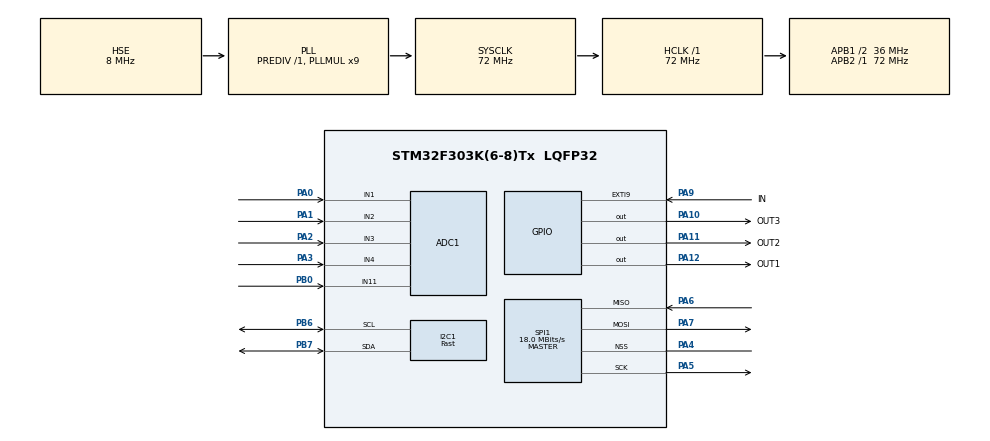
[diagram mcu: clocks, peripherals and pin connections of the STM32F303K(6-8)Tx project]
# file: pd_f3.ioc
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ADC1.Channel-0\#ChannelRegularConversion=ADC_CHANNEL_1
ADC1.Channel-1\#ChannelRegularConversion=ADC_CHANNEL_2
ADC1.Channel-2\#ChannelRegularConversion=ADC_CHANNEL_3
ADC1.Channel-3\#ChannelRegularConversion=ADC_CHANNEL_4
ADC1.Channel-4\#ChannelRegularConversion=ADC_CHANNEL_11
ADC1.ClockPrescaler=ADC_CLOCKPRESCALER_PCLK_DIV2
ADC1.ContinuousConvMode=ENABLE
ADC1.DMAContinuousRequests=ENABLE
ADC1.DataAlign=ADC_DATAALIGN_RIGHT
ADC1.DiscontinuousConvMode=DISABLE
ADC1.EOCSelection=EOC_SEQ_CONV
ADC1.EnableAnalogWatchDog1=false
ADC1.EnableAnalogWatchDog2=false
ADC1.EnableAnalogWatchDog3=false
ADC1.EnableInjectedConversion=ENABLE
ADC1.EnableRegularConversion=ENABLE
ADC1.ExternalTrigConvEdge=ADC_EXTERNALTRIGCONVEDGE_NONE
ADC1.InjNumberOfConversion=0
ADC1.LowPowerAutoWait=DISABLE
ADC1.NbrOfConversion=5
ADC1.NbrOfConversionFlag=1
ADC1.Offset-0\#ChannelRegularConversion=0
ADC1.Offset-1\#ChannelRegularConversion=0
ADC1.Offset-2\#ChannelRegularConversion=0
ADC1.Offset-3\#ChannelRegularConversion=0
ADC1.Offset-4\#ChannelRegularConversion=0
ADC1.OffsetNumber-0\#ChannelRegularConversion=ADC_OFFSET_NONE
ADC1.OffsetNumber-1\#ChannelRegularConversion=ADC_OFFSET_NONE
ADC1.OffsetNumber-2\#ChannelRegularConversion=ADC_OFFSET_NONE
ADC1.OffsetNumber-3\#ChannelRegularConversion=ADC_OFFSET_NONE
ADC1.OffsetNumber-4\#ChannelRegularConversion=ADC_OFFSET_NONE
ADC1.Overrun=OVR_DATA_OVERWRITTEN
ADC1.Rank-0\#ChannelRegularConversion=1
ADC1.Rank-1\#ChannelRegularConversion=2
ADC1.Rank-2\#ChannelRegularConversion=3
ADC1.Rank-3\#ChannelRegularConversion=4
ADC1.Rank-4\#ChannelRegularConversion=5
ADC1.Resolution=ADC_RESOLUTION12b
ADC1.SamplingTime-0\#ChannelRegularConversion=ADC_SAMPLETIME_61CYCLES_5
ADC1.SamplingTime-1\#ChannelRegularConversion=ADC_SAMPLETIME_61CYCLES_5
ADC1.SamplingTime-2\#ChannelRegularConversion=ADC_SAMPLETIME_61CYCLES_5
ADC1.SamplingTime-3\#ChannelRegularConversion=ADC_SAMPLETIME_61CYCLES_5
ADC1.SamplingTime-4\#ChannelRegularConversion=ADC_SAMPLETIME_61CYCLES_5
ADC1.ScanConvMode=ADC_SCAN_ENABLE
ADC1.master=1
Dma.ADC1.3.Direction=DMA_PERIPH_TO_MEMORY
Dma.ADC1.3.Instance=DMA1_Channel1
Dma.ADC1.3.MemDataAlignment=DMA_MDATAALIGN_HALFWORD
Dma.ADC1.3.MemInc=DMA_MINC_ENABLE
Dma.ADC1.3.Mode=DMA_CIRCULAR
Dma.ADC1.3.PeriphDataAlignment=DMA_PDATAALIGN_HALFWORD
Dma.ADC1.3.PeriphInc=DMA_PINC_DISABLE
Dma.ADC1.3.Priority=DMA_PRIORITY_HIGH
Dma.I2C1_RX.0.DMA_Remap=HAL_REMAPDMA_I2C1_RX_DMA1_CH5
Dma.I2C1_RX.0.Direction=DMA_PERIPH_TO_MEMORY
Dma.I2C1_RX.0.Instance=DMA1_Channel5
Dma.I2C1_RX.0.MemDataAlignment=DMA_MDATAALIGN_BYTE
Dma.I2C1_RX.0.MemInc=DMA_MINC_ENABLE
Dma.I2C1_RX.0.Mode=DMA_NORMAL
Dma.I2C1_RX.0.PeriphDataAlignment=DMA_PDATAALIGN_BYTE
Dma.I2C1_RX.0.PeriphInc=DMA_PINC_DISABLE
Dma.I2C1_RX.0.Priority=DMA_PRIORITY_VERY_HIGH
Dma.I2C1_TX.1.DMA_Remap=HAL_REMAPDMA_I2C1_TX_DMA1_CH2
Dma.I2C1_TX.1.Direction=DMA_MEMORY_TO_PERIPH
Dma.I2C1_TX.1.Instance=DMA1_Channel2
Dma.I2C1_TX.1.MemDataAlignment=DMA_MDATAALIGN_BYTE
Dma.I2C1_TX.1.MemInc=DMA_MINC_ENABLE
Dma.I2C1_TX.1.Mode=DMA_NORMAL
Dma.I2C1_TX.1.PeriphDataAlignment=DMA_PDATAALIGN_BYTE
Dma.I2C1_TX.1.PeriphInc=DMA_PINC_DISABLE
Dma.I2C1_TX.1.Priority=DMA_PRIORITY_VERY_HIGH
Dma.Request0=I2C1_RX
Dma.Request1=I2C1_TX
Dma.Request2=SPI1_TX
Dma.Request3=ADC1
Dma.SPI1_TX.2.Direction=DMA_MEMORY_TO_PERIPH
Dma.SPI1_TX.2.Instance=DMA1_Channel3
Dma.SPI1_TX.2.MemDataAlignment=DMA_MDATAALIGN_HALFWORD
Dma.SPI1_TX.2.MemInc=DMA_MINC_ENABLE
Dma.SPI1_TX.2.Mode=DMA_NORMAL
Dma.SPI1_TX.2.PeriphDataAlignment=DMA_PDATAALIGN_HALFWORD
Dma.SPI1_TX.2.PeriphInc=DMA_PINC_DISABLE
Dma.SPI1_TX.2.Priority=DMA_PRIORITY_LOW
FREERTOS.BinarySemaphores01=semI2cBusy
FREERTOS.HEAP_NUMBER=1
FREERTOS.Queues01=qI2cTrans,10,uint32_t,NULL;qAnalyzeCom,10,uint32_t,NULL;qAnalyzeConf,1,Configure,NULL
FREERTOS.Tasks01=defaultTask,0,128,StartDefaultTask;analyze,0,256,Analyze;i2cTrans,1,128,I2cTrans
FREERTOS.configIDLE_SHOULD_YIELD=0
FREERTOS.configQUEUE_REGISTRY_SIZE=0
FREERTOS.configTOTAL_HEAP_SIZE=5000
FREERTOS.configUSE_COUNTING_SEMAPHORES=0
FREERTOS.configUSE_MUTEXES=0
FREERTOS.configUSE_RECURSIVE_MUTEXES=0
I2C1.DualAddressMode=I2C_DUALADDRESS_ENABLED
I2C1.GeneralCallMode=I2C_GENERALCALL_DISABLED
I2C1.I2C_Speed_Mode=I2C_Fast
I2C1.OwnAddress2=1
I2C1.Timing=0x0000020B
Mcu.Family=STM32F3
Mcu.Name=STM32F303K(6-8)Tx
Mcu.Package=LQFP32
NVIC.DMA1_Channel1_IRQn=true\:6\:0\:true
NVIC.DMA1_Channel2_IRQn=true\:7\:0\:true
NVIC.DMA1_Channel3_IRQn=true\:6\:0\:true
NVIC.DMA1_Channel5_IRQn=true\:7\:0\:true
NVIC.EXTI9_5_IRQn=true\:5\:0\:false
NVIC.I2C1_ER_IRQn=true\:5\:0\:false
NVIC.I2C1_EV_IRQn=true\:7\:0\:true
NVIC.PriorityGroup=NVIC_PRIORITYGROUP_4
PA0.Mode=IN1-Single-Ended
PA0.Signal=ADC1_IN1
PA1.Mode=IN2-Single-Ended
PA1.Signal=ADC1_IN2
PA10.GPIO_Label=OUT3
PA10.GPIO_PuPd=GPIO_PULLDOWN
PA10.GPIO_Speed=GPIO_SPEED_HIGH
PA10.Signal=GPIO_Output
PA11.GPIO_Label=OUT2
PA11.GPIO_PuPd=GPIO_PULLDOWN
PA11.GPIO_Speed=GPIO_SPEED_HIGH
PA11.Signal=GPIO_Output
PA12.GPIO_Label=OUT1
PA12.GPIO_PuPd=GPIO_PULLDOWN
PA12.GPIO_Speed=GPIO_SPEED_HIGH
PA12.Signal=GPIO_Output
PA13.Mode=JTAG(5-pin)
PA13.Signal=SYS_JTMS-SWDIO
PA14.Mode=JTAG(5-pin)
PA14.Signal=SYS_JTCK-SWCLK
PA15.Mode=JTAG(5-pin)
PA15.Signal=SYS_JTDI
PA2.Mode=IN3-Single-Ended
PA2.Signal=ADC1_IN3
PA3.Mode=IN4-Single-Ended
PA3.Signal=ADC1_IN4
PA4.Mode=NSS_Signal_Hard
PA4.Signal=SPI1_NSS
PA5.Mode=Full_Duplex_Master
PA5.Signal=SPI1_SCK
PA6.Mode=Full_Duplex_Master
PA6.Signal=SPI1_MISO
PA7.Mode=Full_Duplex_Master
PA7.Signal=SPI1_MOSI
PA9.GPIO_Label=IN
PA9.GPIO_ModeDefaultEXTI=GPIO_MODE_IT_RISING
PA9.GPIO_PuPd=GPIO_PULLDOWN
PA9.Signal=GPXTI9
PB0.Mode=IN11-Single-Ended
PB0.Signal=ADC1_IN11
PB3.Mode=JTAG(5-pin)
PB3.Signal=SYS_JTDO-TRACESWO
PB4.Mode=JTAG(5-pin)
PB4.Signal=SYS_NJTRST
PB6.Mode=I2C
PB6.Signal=I2C1_SCL
PB7.Mode=I2C
PB7.Signal=I2C1_SDA
PF0\ /\ OSC_IN.Mode=HSE-External-Oscillator
PF0\ /\ OSC_IN.Signal=RCC_OSC_IN
PF1\ /\ OSC_OUT.Mode=HSE-External-Oscillator
PF1\ /\ OSC_OUT.Signal=RCC_OSC_OUT
ProjectManager.TargetToolchain=SW4STM32
RCC.ADC12PRES=RCC_ADC12PLLCLK_DIV10
RCC.AHBFreq_Value=72000000
RCC.APB1CLKDivider=RCC_HCLK_DIV2
RCC.APB1Freq_Value=36000000
RCC.APB1TimCLKDivider=1
RCC.APB1TimFreq_Value=36000000
RCC.APB2Freq_Value=72000000
RCC.APB2TimFreq_Value=72000000
RCC.CortexFreq_Value=72000000
RCC.HCLKFreq_Value=72000000
RCC.HSE_VALUE=8000000
RCC.HSI_VALUE=8000000
RCC.PLLMUL=RCC_PLL_MUL9
RCC.PLLSourceVirtual=RCC_PLLSOURCE_HSE
RCC.SYSCLKFreq_VALUE=72000000
RCC.SYSCLKSourceVirtual=RCC_SYSCLKSOURCE_PLLCLK
SPI1.BaudRatePrescaler=SPI_BAUDRATEPRESCALER_4
SPI1.CalculateBaudRate=18.0 MBits/s
SPI1.DataSize=SPI_DATASIZE_16BIT
SPI1.Mode=SPI_MODE_MASTER
SPI1.NSS=SPI_NSS_HARD_OUTPUT
SPI1.VirtualNSS=VM_NSSHARD
VP_FREERTOS_VS_ENABLE.Mode=Enabled
board=pd_f3

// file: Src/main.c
/**
 ******************************************************************************
 * File Name          : main.c
 * Description        : Main program body
 ******************************************************************************
 *
 * COPYRIGHT(c) 2016 STMicroelectronics
 *
 * Redistribution and use in source and binary forms, with or without modification,
 * are permitted provided that the following conditions are met:
 *   1. Redistributions of source code must retain the above copyright notice,
 *      this list of conditions and the following disclaimer.
 *   2. Redistributions in binary form must reproduce the above copyright notice,
 *      this list of conditions and the following disclaimer in the documentation
 *      and/or other materials provided with the distribution.
 *   3. Neither the name of STMicroelectronics nor the names of its contributors
 *      may be used to endorse or promote products derived from this software
 *      without specific prior written permission.
 *
 * THIS SOFTWARE IS PROVIDED BY THE COPYRIGHT HOLDERS AND CONTRIBUTORS "AS IS"
 * AND ANY EXPRESS OR IMPLIED WARRANTIES, INCLUDING, BUT NOT LIMITED TO, THE
 * IMPLIED WARRANTIES OF MERCHANTABILITY AND FITNESS FOR A PARTICULAR PURPOSE ARE
 * DISCLAIMED. IN NO EVENT SHALL THE COPYRIGHT HOLDER OR CONTRIBUTORS BE LIABLE
 * FOR ANY DIRECT, INDIRECT, INCIDENTAL, SPECIAL, EXEMPLARY, OR CONSEQUENTIAL
 * DAMAGES (INCLUDING, BUT NOT LIMITED TO, PROCUREMENT OF SUBSTITUTE GOODS OR
 * SERVICES; LOSS OF USE, DATA, OR PROFITS; OR BUSINESS INTERRUPTION) HOWEVER
 * CAUSED AND ON ANY THEORY OF LIABILITY, WHETHER IN CONTRACT, STRICT LIABILITY,
 * OR TORT (INCLUDING NEGLIGENCE OR OTHERWISE) ARISING IN ANY WAY OUT OF THE USE
 * OF THIS SOFTWARE, EVEN IF ADVISED OF THE POSSIBILITY OF SUCH DAMAGE.
 *
 ******************************************************************************
 */
#include "stm32f3xx_hal.h"
#include "cmsis_os.h"
/* USER CODE BEGIN Includes */
#include "configure.h"
/* USER CODE END Includes */

ADC_HandleTypeDef hadc1;
DMA_HandleTypeDef hdma_adc1;

I2C_HandleTypeDef hi2c1;
DMA_HandleTypeDef hdma_i2c1_rx;
DMA_HandleTypeDef hdma_i2c1_tx;

SPI_HandleTypeDef hspi1;
DMA_HandleTypeDef hdma_spi1_tx;

osThreadId defaultTaskHandle;
osThreadId analyzeHandle;
osThreadId i2cTransHandle;
osMessageQId qI2cTransHandle;
osMessageQId qAnalyzeComHandle;
osMailQId qAnalyzeConfHandle;
//osSemaphoreId semI2cBusyHandle;

/* USER CODE BEGIN PV */
/* Private variables ---------------------------------------------------------*/
static uint16_t outOverload[3] = { GPIO_PIN_12 , GPIO_PIN_11, GPIO_PIN_10};	//номера GPIOA выводов, сигнализирующих о перегрузки по току каналов питания МАД
static uint16_t bufData[NUM_ELEM_BUF_DATA] = {1};	//буфер данных, заполняемый показаниями АЦП
static uint16_t* addrBegBufData = bufData;	//адрес начала буфера данных
static uint16_t* addrMeanBufData = bufData + NUM_ELEM_BUF_DATA/2;	//адрес середины буфера данных
static uint16_t* addrEndBufData = bufData + NUM_ELEM_BUF_DATA;	//адрес последнего элемента буфера данных
static struct Sample* addrStopPoint;	//адрес следующей точки остановки мониторинговой программы
static struct Sample* addrCurPoint;	//адрес текущего положения мониторинговой программы
static uint32_t countOfLead;	//счётчик опережения. Используется для определния насколько сегментов мониторинг данных отстал от их заполнения
struct StatusMonitData stMonitData;	//структура, управляющая режимом сбора данных
static struct SecConfigure bufConf;	//буфер, в котором сохраняется полученное по I2C новое значение структуры безопасности
static uint32_t bufCom;	//буфер, в котором сохраняется полученная по I2C очередная команда
static uint32_t identBlockDataComForI2c;	//идентификатор блока данных, пришедшего по i2c
static uint32_t bufI2cTrans = 1;
static bool i2c_is_trans = true;	//флаг режима работы i2c, true - передатчик
/* USER CODE END PV */

void SystemClock_Config(void);
static void MX_GPIO_Init(void);
static void MX_DMA_Init(void);
static void MX_ADC1_Init(void);
static void MX_I2C1_Init(void);
static void MX_SPI1_Init(void);
void Analyze(void const * argument);
void I2cTrans(void const * argument);

/* USER CODE BEGIN PFP */
/* Private function prototypes -----------------------------------------------*/
void initMonitorSwitchParams(struct MonitSwitchModeParams* pMonitSwMPs, struct SecConfigure* pConf); //инициализация pMonitSwMPs в соответствие с новой конфигурацией безопасности
void initTracking(struct MonitSwitchModeParams* pMonitSwMPs, struct SecConfigure* pConf);	//предварительная подготовка перед стартом мониторинга
enum SWITCH_MODE checkCurrentMads(uint16_t val, const struct MCur* pMCur, struct MonitSwitchMode* pMonit);	//управление переключением режима безопасности параметра ток МАД
enum SWITCH_MODE checkVoltage(uint16_t val, const struct Volt* pVol, struct MonitSwitchMode* pMonit);	//управление переключением режима безопасности параметра напряжение
void monitoringSample(const struct Sample* pSample, const struct SecConfigure* pConf, struct MonitSwitchModeParams* mSwitchModePs);	//мониторинг одного отсчёта
void startTracking(void);	//применяется при старте/рестарте процедуры отслеживания параметров питания
void sendMesOverrunAdc(void);	//сообщить мониторинговой подпрограмме о перегрузке АЦП
void sendMesSpiNotTime(void);	//сообщить мониторинговой подпрограмме о том, что передача данных  в SPI порт не успевает вовремя закончится при текущей скорости потока
void setStMonitData(struct StatusMonitData st); //установить новое значение структуры, управляющей режимом сбора данных
void enableSpiTrans(void);	//разрешение передавать данные по spi
void disableSpiTrans(void);	//запрет передавать данные по spi
void countOfLeadSetZero(void);	//обнуление счётчика опережения
void countOfLeadInc(void);	//инкрементирование счётчика опережения
void countOfLeadDec(void); //декрементировать счётчик опережения
uint32_t countOfLeadRead(void); //прочитать счётчик опережения
struct Sample* getCurAddrDmaAdc(void);	//сообщает текущий адрес заполнения DMA ADC
void setStopPointAtBegSegment(void);	//установить точку останова в начало следующего сегмента
void setTestPinPB1(void);
void setTestPinPA8(void);
void temp_setSecConfigure(struct SecConfigure* sec);

/* USER CODE END PFP */

/* USER CODE BEGIN 0 */
HAL_StatusTypeDef User_SPI_Transmit_DMA(SPI_HandleTypeDef *hspi, uint16_t *pData, uint16_t Size) {	//передача данных в SPI используя DMA без прерываний
	if((hdma_spi1_tx.Instance->CNDTR != 0)	//проверка, что SPI передача данных уже не активна
			|| ((hspi->Instance->SR & SPI_SR_FTLVL) != SPI_FRLVL_EMPTY)
			|| ((hspi->Instance->SR & SPI_FLAG_BSY) !=  RESET ) )
		return HAL_ERROR;
	__HAL_DMA_DISABLE(&hdma_spi1_tx);
	/* Configure DMA Channel data length */
	hdma_spi1_tx.Instance->CNDTR = Size;
	/* Configure DMA Channel source address */
	hdma_spi1_tx.Instance->CMAR = (uint32_t)pData;
	__HAL_DMA_ENABLE(&hdma_spi1_tx);
	return HAL_OK;
}

void ADCIntCallback(void) {
	if(__HAL_ADC_GET_FLAG(&hadc1, ADC_FLAG_OVR)) {
		sendMesOverrunAdc();
	}
}

void getInfoBufConf(uint8_t** addr, size_t* pSize) {
	*addr = (uint8_t*)&bufConf;
	*pSize = sizeof(bufConf);
}

void getInfoBufCom(uint8_t** addr, size_t* pSize){
	*addr = (uint8_t*)&bufCom;
	*pSize = sizeof(bufCom);
}

void setIdentBlockDataComForI2c(uint32_t ident) {
	identBlockDataComForI2c = ident;
}

void HAL_ADC_ConvCpltCallback(ADC_HandleTypeDef* hadc) {
	countOfLeadInc();
	if(stMonitData.isTransDataToSpi != true)
		return;
	if(User_SPI_Transmit_DMA(&hspi1, addrMeanBufData, NUM_ELEM_BUF_DATA/2) == HAL_ERROR) {
		sendMesSpiNotTime();
	}
}

void HAL_ADC_ConvHalfCpltCallback(ADC_HandleTypeDef* hadc) {
	countOfLeadInc();
	if(stMonitData.isTransDataToSpi != true)
		return;
	if(User_SPI_Transmit_DMA(&hspi1, addrBegBufData, NUM_ELEM_BUF_DATA/2) == HAL_ERROR) {
		sendMesSpiNotTime();
	}
}

void HAL_I2C_MasterTxCpltCallback(I2C_HandleTypeDef *hi2c) {
	if(i2c_is_trans == false)
		HAL_I2C_Slave_Receive_IT(hi2c, (uint8_t*)&bufCom, sizeof(bufCom));
}

void HAL_I2C_SlaveRxCpltCallback(I2C_HandleTypeDef *hi2c) {
	struct SecConfigure* pConf;
	if(hi2c->XferSize == 0) {
		switch(identBlockDataComForI2c) {
		case I2C_ADDR_COM:
			osMessagePut(qAnalyzeComHandle, bufCom, 0);
			break;
		case I2C_ADDR_CONF:
			pConf = (struct SecConfigure*)osMailAlloc(qAnalyzeConfHandle, 0);
			if(pConf != NULL) {
				*pConf = bufConf;
				osMailPut(qAnalyzeConfHandle, pConf);
			}
		}
	}
	i2c_is_trans = true;
}
/* USER CODE END 0 */

int main(void)
{

	/* MCU Configuration----------------------------------------------------------*/

	/* Reset of all peripherals, Initializes the Flash interface and the Systick. */
	HAL_Init();

	/* Configure the system clock */
	SystemClock_Config();

	/* Initialize all configured peripherals */
	MX_GPIO_Init();
	MX_DMA_Init();
	MX_ADC1_Init();
	MX_I2C1_Init();
	MX_SPI1_Init();

	/* Create the semaphores(s) */
	/* definition and creation of semI2cBusy */
	//osSemaphoreDef(semI2cBusy);
	//semI2cBusyHandle = osSemaphoreCreate(osSemaphore(semI2cBusy), 1);

	/* Create the thread(s) */

	/* definition and creation of analyze */
	osThreadDef(analyze, Analyze, osPriorityNormal, 0, 256);
	analyzeHandle = osThreadCreate(osThread(analyze), NULL);

	/* definition and creation of i2cTrans */
	osThreadDef(i2cTrans, I2cTrans, osPriorityAboveNormal, 0, 128);
	i2cTransHandle = osThreadCreate(osThread(i2cTrans), NULL);

	/* Create the queue(s) */
	/* definition and creation of qI2cTrans */
	osMessageQDef(qI2cTrans, 20, uint32_t);
	qI2cTransHandle = osMessageCreate(osMessageQ(qI2cTrans), NULL);

	/* definition and creation of qAnalyzeCom */
	osMessageQDef(qAnalyzeCom, 10, uint32_t);
	qAnalyzeComHandle = osMessageCreate(osMessageQ(qAnalyzeCom), NULL);

	/* definition and creation of qAnalyzeConf */
	osMailQDef(qAnalyzeConf, 1, struct SecConfigure);
	qAnalyzeConfHandle = osMailCreate(osMailQ(qAnalyzeConf), NULL);

	/* Start scheduler */
	osKernelStart();

	/* We should never get here as control is now taken by the scheduler */

	/* Infinite loop */
	while (1)
	{

	}

}

/** System Clock Configuration
 */
void SystemClock_Config(void)
{

	RCC_OscInitTypeDef RCC_OscInitStruct;
	RCC_ClkInitTypeDef RCC_ClkInitStruct;
	RCC_PeriphCLKInitTypeDef PeriphClkInit;

	RCC_OscInitStruct.OscillatorType = RCC_OSCILLATORTYPE_HSI|RCC_OSCILLATORTYPE_HSE;
	RCC_OscInitStruct.HSEState = RCC_HSE_ON;
	RCC_OscInitStruct.HSEPredivValue = RCC_HSE_PREDIV_DIV1;
	RCC_OscInitStruct.HSIState = RCC_HSI_ON;
	RCC_OscInitStruct.HSICalibrationValue = 16;
	RCC_OscInitStruct.PLL.PLLState = RCC_PLL_ON;
	RCC_OscInitStruct.PLL.PLLSource = RCC_PLLSOURCE_HSE;
	RCC_OscInitStruct.PLL.PLLMUL = RCC_PLL_MUL9;
	HAL_RCC_OscConfig(&RCC_OscInitStruct);

	RCC_ClkInitStruct.ClockType = RCC_CLOCKTYPE_SYSCLK|RCC_CLOCKTYPE_PCLK1;
	RCC_ClkInitStruct.SYSCLKSource = RCC_SYSCLKSOURCE_PLLCLK;
	RCC_ClkInitStruct.AHBCLKDivider = RCC_SYSCLK_DIV1;
	RCC_ClkInitStruct.APB1CLKDivider = RCC_HCLK_DIV2;
	RCC_ClkInitStruct.APB2CLKDivider = RCC_HCLK_DIV1;
	HAL_RCC_ClockConfig(&RCC_ClkInitStruct, FLASH_LATENCY_2);

	PeriphClkInit.PeriphClockSelection = RCC_PERIPHCLK_I2C1;
	PeriphClkInit.I2c1ClockSelection = RCC_I2C1CLKSOURCE_HSI;
	HAL_RCCEx_PeriphCLKConfig(&PeriphClkInit);

	HAL_SYSTICK_Config(HAL_RCC_GetHCLKFreq()/1000);

	HAL_SYSTICK_CLKSourceConfig(SYSTICK_CLKSOURCE_HCLK);

	/* SysTick_IRQn interrupt configuration */
	HAL_NVIC_SetPriority(SysTick_IRQn, 15, 0);
}

/* ADC1 init function */
void MX_ADC1_Init(void)
{

	ADC_ChannelConfTypeDef sConfig;

	/**Common config
	 */
	hadc1.Instance = ADC1;
	hadc1.Init.ClockPrescaler = ADC_CLOCKPRESCALER_PCLK_DIV2;
	hadc1.Init.Resolution = ADC_RESOLUTION12b;
	hadc1.Init.ScanConvMode = ADC_SCAN_ENABLE;
	hadc1.Init.ContinuousConvMode = ENABLE;
	hadc1.Init.DiscontinuousConvMode = DISABLE;
	hadc1.Init.ExternalTrigConvEdge = ADC_EXTERNALTRIGCONVEDGE_NONE;
	hadc1.Init.DataAlign = ADC_DATAALIGN_RIGHT;
	hadc1.Init.NbrOfConversion = 5;
	hadc1.Init.DMAContinuousRequests = ENABLE;
	hadc1.Init.EOCSelection = EOC_SEQ_CONV;
	hadc1.Init.LowPowerAutoWait = DISABLE;
	hadc1.Init.Overrun = OVR_DATA_PRESERVED;
	HAL_ADC_Init(&hadc1);

	/**Configure Regular Channel
	 */
	sConfig.Channel = ADC_CHANNEL_1;
	sConfig.Rank = 1;
	sConfig.SingleDiff = ADC_SINGLE_ENDED;
	sConfig.SamplingTime = ADC_SAMPLETIME_61CYCLES_5;
	sConfig.OffsetNumber = ADC_OFFSET_NONE;
	sConfig.Offset = 0;
	HAL_ADC_ConfigChannel(&hadc1, &sConfig);

	/**Configure Regular Channel
	 */
	sConfig.Channel = ADC_CHANNEL_2;
	sConfig.Rank = 2;
	HAL_ADC_ConfigChannel(&hadc1, &sConfig);

	/**Configure Regular Channel
	 */
	sConfig.Channel = ADC_CHANNEL_3;
	sConfig.Rank = 3;
	HAL_ADC_ConfigChannel(&hadc1, &sConfig);

	/**Configure Regular Channel
	 */
	sConfig.Channel = ADC_CHANNEL_4;
	sConfig.Rank = 4;
	HAL_ADC_ConfigChannel(&hadc1, &sConfig);

	/**Configure Regular Channel
	 */
	sConfig.Channel = ADC_CHANNEL_11;
	sConfig.Rank = 5;
	HAL_ADC_ConfigChannel(&hadc1, &sConfig);

	/* EXTI interrupt init*/
	HAL_NVIC_SetPriority(ADC1_2_IRQn, 5, 0);
	HAL_NVIC_EnableIRQ(ADC1_2_IRQn);
}

/* I2C1 init function */
void MX_I2C1_Init(void)
{

	hi2c1.Instance = I2C1;
	hi2c1.Init.Timing = 0x0000020B;
	hi2c1.Init.OwnAddress1 = I2C_ADDR_CONF;
	hi2c1.Init.AddressingMode = I2C_ADDRESSINGMODE_7BIT;
	hi2c1.Init.DualAddressMode = I2C_DUALADDRESS_ENABLED;
	hi2c1.Init.OwnAddress2 = I2C_ADDR_COM;
	hi2c1.Init.OwnAddress2Masks = I2C_OA2_NOMASK;
	hi2c1.Init.GeneralCallMode = I2C_GENERALCALL_DISABLED;
	hi2c1.Init.NoStretchMode = I2C_NOSTRETCH_DISABLED;
	HAL_I2C_Init(&hi2c1);

	/**Configure Analogue filter
	 */
	HAL_I2CEx_AnalogFilter_Config(&hi2c1, I2C_ANALOGFILTER_ENABLED);

}

/* SPI1 init function */
void MX_SPI1_Init(void)
{

	hspi1.Instance = SPI1;
	hspi1.Init.Mode = SPI_MODE_MASTER;
	hspi1.Init.Direction = SPI_DIRECTION_2LINES;
	hspi1.Init.DataSize = SPI_DATASIZE_16BIT;
	hspi1.Init.CLKPolarity = SPI_POLARITY_LOW;
	hspi1.Init.CLKPhase = SPI_PHASE_1EDGE;
	hspi1.Init.NSS = SPI_NSS_HARD_OUTPUT;
	hspi1.Init.BaudRatePrescaler = SPI_BAUDRATEPRESCALER_8;
	hspi1.Init.FirstBit = SPI_FIRSTBIT_MSB;
	hspi1.Init.TIMode = SPI_TIMODE_DISABLED;
	hspi1.Init.CRCCalculation = SPI_CRCCALCULATION_DISABLED;
	hspi1.Init.CRCPolynomial = 10;
	hspi1.Init.CRCLength = SPI_CRC_LENGTH_DATASIZE;
	hspi1.Init.NSSPMode = SPI_NSS_PULSE_ENABLED;
	HAL_SPI_Init(&hspi1);
	__HAL_SPI_ENABLE(&hspi1);

}

void MX_DMA_Init(void)
{
	/* DMA controller clock enable */
	__DMA1_CLK_ENABLE();

	/* DMA interrupt init */
	HAL_NVIC_SetPriority(DMA1_Channel1_IRQn, 6, 0);
	HAL_NVIC_EnableIRQ(DMA1_Channel1_IRQn);
	HAL_NVIC_SetPriority(DMA1_Channel2_IRQn, 7, 0);
	HAL_NVIC_EnableIRQ(DMA1_Channel2_IRQn);
	//HAL_NVIC_SetPriority(DMA1_Channel3_IRQn, 6, 0);
	//HAL_NVIC_EnableIRQ(DMA1_Channel3_IRQn);
	HAL_NVIC_SetPriority(DMA1_Channel5_IRQn, 7, 0);
	HAL_NVIC_EnableIRQ(DMA1_Channel5_IRQn);

}

/** Configure pins as
 * Analog
 * Input
 * Output
 * EVENT_OUT
 * EXTI
 */
void MX_GPIO_Init(void)
{

	GPIO_InitTypeDef GPIO_InitStruct;

	/* GPIO Ports Clock Enable */
	__GPIOF_CLK_ENABLE();
	__GPIOA_CLK_ENABLE();
	__GPIOB_CLK_ENABLE();

	/*Configure GPIO pin : IN_Pin */
	GPIO_InitStruct.Pin = IN_Pin;
	GPIO_InitStruct.Mode = GPIO_MODE_IT_RISING;
	GPIO_InitStruct.Pull = GPIO_PULLDOWN;
	HAL_GPIO_Init(IN_GPIO_Port, &GPIO_InitStruct);

	/*Configure GPIO pins : OUT3_Pin OUT2_Pin OUT1_Pin */
	GPIO_InitStruct.Pin = OUT3_Pin|OUT2_Pin|OUT1_Pin;
	GPIO_InitStruct.Mode = GPIO_MODE_OUTPUT_PP;
	GPIO_InitStruct.Pull = GPIO_PULLDOWN;
	GPIO_InitStruct.Speed = GPIO_SPEED_HIGH;
	HAL_GPIO_Init(GPIOA, &GPIO_InitStruct);

	/*Configure test GPIO pins */
	GPIO_InitStruct.Pin = GPIO_PIN_1;
	GPIO_InitStruct.Mode = GPIO_MODE_OUTPUT_PP;
	GPIO_InitStruct.Pull = GPIO_PULLDOWN;
	GPIO_InitStruct.Speed = GPIO_SPEED_HIGH;
	HAL_GPIO_Init(GPIOB, &GPIO_InitStruct);

	GPIO_InitStruct.Pin = GPIO_PIN_8;
	GPIO_InitStruct.Mode = GPIO_MODE_OUTPUT_PP;
	GPIO_InitStruct.Pull = GPIO_PULLDOWN;
	GPIO_InitStruct.Speed = GPIO_SPEED_HIGH;
	HAL_GPIO_Init(GPIOA, &GPIO_InitStruct);

	/* EXTI interrupt init*/
	HAL_NVIC_SetPriority(EXTI9_5_IRQn, 5, 0);
	HAL_NVIC_EnableIRQ(EXTI9_5_IRQn);

}

/* USER CODE BEGIN 4 */
void initMonitorSwitchParams(struct MonitSwitchModeParams* pMonitSwMPs, struct SecConfigure* pConf) {
	union I2cMes mes;
	for(int i = 0; i < 3; i++) {
		pMonitSwMPs->mCur[i].isSecMode = true;
		pMonitSwMPs->mCur[i].whileInOthMode = pConf->mads[i].time_overh;
	}
	pMonitSwMPs->v_48.isSecMode = false;
	pMonitSwMPs->v_48.whileInOthMode = pConf->v_48.time_overh;
	pMonitSwMPs->v_300.isSecMode = false;
	pMonitSwMPs->v_300.whileInOthMode = pConf->v_300.time_overh;
	for(int i = 0; i < 3; i++)
		HAL_GPIO_WritePin(GPIOA, outOverload[i], GPIO_PIN_RESET);
	mes.frame.id = MES_VOLT_300V_TO_UNSEC_MODE;
	mes.frame.arg = 0;
	osMessagePut(qI2cTransHandle, mes.blob, 0);
	mes.frame.id = MES_VOLT_48V_TO_UNSEC_MODE;
	osMessagePut(qI2cTransHandle, mes.blob, 0);
}

void initTracking(struct MonitSwitchModeParams* pMonitSwMPs, struct SecConfigure* pConf) {
	HAL_ADC_Stop_DMA(&hadc1);
	addrStopPoint = (struct Sample*)addrBegBufData;
	addrCurPoint = (struct Sample*)addrBegBufData;
	initMonitorSwitchParams(pMonitSwMPs, pConf);
	struct StatusMonitData st;
	st.isTransDataToSpi = false;
	st.isValidConfig = true;
	setStMonitData(st);
	countOfLead = 0;	//обнуление счётчика опережения
	while((hdma_spi1_tx.Instance->CNDTR != 0)	//ожидание завершения активности SPI передачи данных
			|| ((hspi1.Instance->SR & SPI_SR_FRLVL) != SPI_FRLVL_EMPTY)
			|| ((hspi1.Instance->SR & SPI_FLAG_BSY) !=  RESET ) ) {
		osDelay(3);
	}
	//HAL_ADC_Start_DMA(&hadc1, (uint32_t*)addrCurPoint, NUM_ELEM_BUF_DATA);
}

enum SWITCH_MODE checkCurrentMads(uint16_t val, const struct MCur* pMCur, struct MonitSwitchMode* pMonit) {
	bool is_SecValue = (val <= pMCur->max);
	if (is_SecValue == pMonit->isSecMode) {
		pMonit->whileInOthMode = pMCur->time_overh;
	} else {
		if(--pMonit->whileInOthMode <= 0) {
			pMonit->isSecMode = is_SecValue;
			pMonit->whileInOthMode = pMCur->time_overh;
			if(is_SecValue)
				return MOVE_TO_SEC_MODE;
			else
				return MOVE_TO_UNSEC_MODE;
		}
	}
	return NO_CHANGE;
}

enum SWITCH_MODE checkVoltage(uint16_t val, const struct Volt* pVol, struct MonitSwitchMode* pMonit) {
	bool is_SecValue = (val <= pVol->max && val >= pVol->min);
	if (is_SecValue == pMonit->isSecMode) {
		pMonit->whileInOthMode = pVol->time_overh;
	} else {
		if(--pMonit->whileInOthMode <= 0) {
			pMonit->isSecMode = is_SecValue;
			pMonit->whileInOthMode = pVol->time_overh;
			if(is_SecValue)
				return MOVE_TO_SEC_MODE;
			else
				return MOVE_TO_UNSEC_MODE;
		}
	}
	return NO_CHANGE;
}

void monitoringSample(const struct Sample* pSample, const struct SecConfigure* pConf, struct MonitSwitchModeParams* mSwitchModePs) {
	static enum SWITCH_MODE swMode;
	static union I2cMes mes;
	//проверка токов потребления МАД на перегрузку
	for(int i = 0; i < 3; i++){
		swMode = checkCurrentMads(pSample->iMad[i], &pConf->mads[i], &mSwitchModePs->mCur[i]);
		switch(swMode) {
		case MOVE_TO_SEC_MODE:
			HAL_GPIO_WritePin(GPIOA, outOverload[i], GPIO_PIN_SET);
			break;
		case MOVE_TO_UNSEC_MODE:
			HAL_GPIO_WritePin(GPIOA, outOverload[i], GPIO_PIN_RESET);
			break;
		case NO_CHANGE:
			break;
		}
	}
	//проверка мониторируемого напряжения 48В на соответствие безопасному режиму
	swMode = checkVoltage(pSample->u48v, &pConf->v_48, &mSwitchModePs->v_48);
	switch(swMode) {
	case MOVE_TO_SEC_MODE:
		mes.frame.id = MES_VOLT_48V_TO_SEC_MODE;
		mes.frame.arg = pSample->u48v;
		osMessagePut(qI2cTransHandle, mes.blob, 0);
		break;
	case MOVE_TO_UNSEC_MODE:
		mes.frame.id = MES_VOLT_48V_TO_UNSEC_MODE;
		mes.frame.arg = pSample->u48v;
		osMessagePut(qI2cTransHandle, mes.blob, 0);
		break;
	case NO_CHANGE:
		break;
	}
	//проверка мониторируемого напряжения 300В на соответствие безопасному режиму
	swMode = checkVoltage(pSample->u300v, &pConf->v_300, &mSwitchModePs->v_300);
	switch(swMode) {
	case MOVE_TO_SEC_MODE:
		mes.frame.id = MES_VOLT_300V_TO_SEC_MODE;
		mes.frame.arg = pSample->u300v;
		osMessagePut(qI2cTransHandle, mes.blob, 0);
		break;
	case MOVE_TO_UNSEC_MODE:
		mes.frame.id = MES_VOLT_300V_TO_UNSEC_MODE;
		mes.frame.arg = pSample->u300v;
		osMessagePut(qI2cTransHandle, mes.blob, 0);
		break;
	case NO_CHANGE:
		break;
	}
}

void startTracking(void) {
	HAL_ADC_Start_DMA(&hadc1, (uint32_t*)addrBegBufData, NUM_ELEM_BUF_DATA);
}

void sendMesOverrunAdc(void) {
	union I2cMes mes;
	mes.frame.id = MES_OVR_ADC;
	osMessagePut(qAnalyzeComHandle, mes.blob, 0);
}

void sendMesSpiNotTime(void) {
	union I2cMes mes;
	mes.frame.id = MES_SPI_TRANS_NOT_TIME;
	osMessagePut(qAnalyzeComHandle, mes.blob, 0);
}

void setStMonitData(struct StatusMonitData st) {
	taskENTER_CRITICAL();
	stMonitData = st;
	taskEXIT_CRITICAL();
}

void enableSpiTrans(void) {
	taskENTER_CRITICAL();
	stMonitData.isTransDataToSpi = true;
	taskEXIT_CRITICAL();
}

void disableSpiTrans(void) {
	taskENTER_CRITICAL();
	stMonitData.isTransDataToSpi = false;
	taskEXIT_CRITICAL();
}

void countOfLeadSetZero(void) {
	taskDISABLE_INTERRUPTS();
	countOfLead = 0;
	taskENABLE_INTERRUPTS();
}

void countOfLeadInc(void) {
	taskDISABLE_INTERRUPTS();
	if(countOfLead < MAX_VAL_COUNT_LEAD)
		++countOfLead;
	taskENABLE_INTERRUPTS();
}

void countOfLeadDec(void) {
	taskDISABLE_INTERRUPTS();
	if(countOfLead > 0)
		--countOfLead;
	taskENABLE_INTERRUPTS();
}

uint32_t countOfLeadRead(void) {
	return countOfLead;
}

struct Sample* getCurAddrDmaAdc(void) {
	uint32_t n = NUM_ELEM_BUF_DATA - hdma_adc1.Instance->CNDTR;
	return (struct Sample*)addrBegBufData + n/5;
}

void setStopPointAtBegSegment(void) {
	if(addrCurPoint < (struct Sample*)addrMeanBufData)
		addrStopPoint = (struct Sample*)addrMeanBufData;
	else if(addrCurPoint < (struct Sample*)addrEndBufData)
		addrStopPoint = (struct Sample*)addrEndBufData;
	else {
		addrCurPoint = (struct Sample*)addrBegBufData;
		addrStopPoint = (struct Sample*)addrMeanBufData;
	}
}

void setTestPinPB1(void) {
	HAL_GPIO_WritePin(GPIOB, GPIO_PIN_1, GPIO_PIN_SET);
}

void setTestPinPA8(void) {
	HAL_GPIO_WritePin(GPIOA, GPIO_PIN_8, GPIO_PIN_SET);
}

void temp_setSecConfigure(struct SecConfigure* sec) {
	sec->v_48.max = 65535;
	sec->v_48.min = 0;
	sec->v_48.time_overh = 10;
	sec->v_300.max = 65535;
	sec->v_300.min = 0;
	sec->v_300.time_overh = 10;
	for(int i = 0; i < 3; i++) {
		sec->mads[i].max = 65535;
		sec->mads[i].time_overh = 10;
	}
	stMonitData.isValidConfig = true;
}
/* USER CODE END 4 */

/* Analyze function */
void Analyze(void const * argument)
{
	/* USER CODE BEGIN Analyze */
	static struct SecConfigure confSecure;
	static struct MonitSwitchModeParams mSwitchModePs;
	static union I2cMes mes;
	static uint32_t tick;
	static osEvent event;
	static struct SecConfigure* pConf;
	countOfLeadSetZero();
	tick = osKernelSysTick() + osKernelSysTickMicroSec(TIME_TRANS_REQ_CONFIGURE);
	stMonitData.isValidConfig = false;

	//код, тестирующий начало мониторинга
	/*temp_setSecConfigure(&confSecure);
	initTracking(&mSwitchModePs, &confSecure);
	enableSpiTrans();
	startTracking();*/

	for(;;) {
		//чтение из очереди конфигурации
		event = osMailGet(qAnalyzeConfHandle, 0);
		if(event.status == osEventMail) {
			pConf = (struct SecConfigure*)event.value.p;
			confSecure = *pConf;
			osMailFree(qAnalyzeConfHandle, pConf);
			initTracking(&mSwitchModePs, &confSecure);
			startTracking();
			setTestPinPA8();
		}
		//проверка находится ли программа в начале процедуры запуска
		if(!stMonitData.isValidConfig) {
			if(osKernelSysTick() >= tick) {
				tick = tick + osKernelSysTickMicroSec(TIME_TRANS_REQ_CONFIGURE);
				mes.frame.id = MES_GET_CONFIGURE;
				mes.frame.arg = TIME_TRANS_REQ_CONFIGURE/1000;
				osMessagePut(qI2cTransHandle, mes.blob, 0);
			}
			continue;
		}
		//чтение сообщений из очереди команд
		event = osMessageGet (qAnalyzeComHandle, 0);
		if(event.status == osEventMessage) {
			mes.blob = event.value.v;
			switch(mes.frame.id) {
			case MES_OVR_ADC:
			case MES_SPI_TRANS_NOT_TIME:
				initTracking(&mSwitchModePs, &confSecure);
				osMessagePut(qI2cTransHandle, mes.blob, 0);
				break;
			case MES_DISABLE_TRANS_MONIT_DATA:
				disableSpiTrans();
				break;
			case MES_ENABLE_TRANS_MONIT_DATA:
				enableSpiTrans();
				setTestPinPB1();
				break;
			case MES_START_MONIT_DATA:
				startTracking();
				break;
			}
		}
		//проверка достиг ли счётчик адресов начала полубуфера
		if(addrCurPoint == (struct Sample*)addrBegBufData || addrCurPoint == (struct Sample*)addrMeanBufData)
			countOfLeadDec();
		//проверка достигнута ли точка останова
		if(addrCurPoint >= addrStopPoint) {
			switch(countOfLeadRead()) {
			case 0:
				addrStopPoint = getCurAddrDmaAdc();
				break;
			case 1:
				setStopPointAtBegSegment();
				break;
			case 2:
				if(addrCurPoint > getCurAddrDmaAdc()) {
					addrStopPoint = (struct Sample*)addrEndBufData;
					break;
				}
				/* no break */
			case 3:
				mes.frame.id = MES_MONIT_NOT_TIME;
				osMessagePut(qI2cTransHandle, mes.blob, 0);
				taskENTER_CRITICAL();
				addrStopPoint = getCurAddrDmaAdc();
				if(addrStopPoint < (struct Sample*)addrMeanBufData)
					addrCurPoint = (struct Sample*)addrBegBufData;
				else
					addrCurPoint = (struct Sample*)addrMeanBufData;
				countOfLeadSetZero();
				taskEXIT_CRITICAL();
				break;
			}

		} else {
			monitoringSample(addrCurPoint, &confSecure, &mSwitchModePs);
			++addrCurPoint;
		}
	}
	/* USER CODE END Analyze */
}

/* I2cTrans function */
void I2cTrans(void const * argument)
{
	/* USER CODE BEGIN I2cTrans */
	/* Infinite loop */
	static osEvent event;
	HAL_StatusTypeDef status;
	for(;;)
	{
		//чтение сообщений из очереди команд
		event = osMessageGet (qI2cTransHandle, osWaitForever);
		if(event.status == osEventMessage) {
			do {
				while(__HAL_I2C_GET_FLAG(&hi2c1, I2C_FLAG_BUSY) == SET || i2c_is_trans == false)
					osDelay(2);
				bufI2cTrans = event.value.v;
				status = HAL_I2C_Master_Transmit_IT(&hi2c1, I2C_ADDR_HOST_MCU, (uint8_t*)&bufI2cTrans, 4);
			} while(status != HAL_OK);
		}
	}
	/* USER CODE END I2cTrans */
}

void HAL_GPIO_EXTI_Callback(uint16_t GPIO_Pin) {
	if(GPIO_Pin == GPIO_PIN_9) {
		i2c_is_trans = false;
		if(__HAL_I2C_GET_FLAG(&hi2c1, I2C_FLAG_BUSY) != SET)
			HAL_I2C_Slave_Receive_IT(&hi2c1, (uint8_t*)&bufCom, sizeof(bufCom));
	}
}

void HAL_I2C_ErrorCallback(I2C_HandleTypeDef *hi2c) {
	if(hi2c == &hi2c1)
		i2c_is_trans = true;
}

/************************ (C) COPYRIGHT STMicroelectronics *****END OF FILE****/
